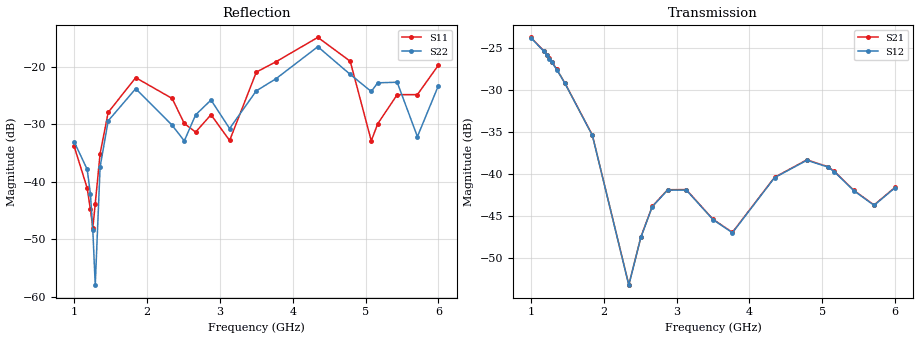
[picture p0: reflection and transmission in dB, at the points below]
!Agilent Technologies,E8364B,MY43040528,A.07.50.67
!Agilent E8364B: A.07.50.67
!Date: Sunday, March 01, 2026 16:46:23
!Correction: S11(Full 2 Port(1,2))
!S21(Full 2 Port(1,2))
!S12(Full 2 Port(1,2))
!S22(Full 2 Port(1,2))
!S2P File: Measurements: S11, S21, S12, S22:
# Hz S  dB  R 50
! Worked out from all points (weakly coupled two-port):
!   451 points, 1 GHz to 6 GHz, reference 50 ohm
!   highest |S21| = -23.77 dB at 1 GHz (marker M1); lowest = -53.3 dB at 2.344 GHz (marker M2)
!   lowest |S11| = -48.0 dB at 1.256 GHz (marker M3), VSWR 1.01, Z = 49.9 + j0.378 ohm
!   |S11| at or under -10 dB: start of sweep to end of sweep
!   |S22| runs from -59.1 to -16.4 dB; largest |S21 - S12| = 0.00031
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1e9  -33.84 31.8  -23.77 153.0  -23.81 153.1  -33.05 -1.2
1.177778e9  -41.06 49.9  -25.39 51.3  -25.43 51.4  -37.80 -5.1
1.222222e9  -44.77 65.2  -25.88 26.0  -25.92 26.1  -42.06 -10.1
1.255556e9  -48.02 107.3  -26.27 7.1  -26.31 7.2  -48.42 -14.6
1.288889e9  -43.80 155.4  -26.69 -11.8  -26.73 -11.7  -57.95 95.5
1.355556e9  -35.07 167.4  -27.58 -49.1  -27.62 -49.0  -37.39 116.5
1.466667e9  -27.91 147.2  -29.20 -110.2  -29.23 -110.2  -29.38 89.8
1.844444e9  -21.87 75.6  -35.42 47.5  -35.46 47.6  -23.79 -4.3
2.344444e9  -25.49 13.5  -53.25 -150.6  -53.29 -150.7  -30.15 -77.0
2.511111e9  -29.84 6.6  -47.52 178.8  -47.57 178.7  -32.87 -58.3
2.666667e9  -31.34 35.4  -43.90 104.3  -43.94 104.3  -28.35 -55.6
2.877778e9  -28.32 30.4  -41.92 -6.0  -41.96 -6.0  -25.76 -96.1
3.133333e9  -32.80 52.1  -41.91 -142.0  -41.96 -141.9  -30.72 -127.7
3.5e9  -20.91 47.2  -45.45 37.0  -45.48 37.2  -24.16 -128.5
3.766667e9  -19.13 21.7  -47.00 -66.1  -47.05 -66.0  -22.09 -156.5
4.344444e9  -14.87 -44.7  -40.45 22.7  -40.49 22.7  -16.49 111.7
4.788889e9  -19.02 -113.7  -38.36 133.9  -38.41 133.9  -21.31 36.2
5.077778e9  -32.86 -103.6  -39.18 -36.7  -39.22 -36.7  -24.28 40.7
5.166667e9  -29.89 -61.1  -39.74 -90.5  -39.79 -90.4  -22.77 33.5
5.433333e9  -24.83 -77.1  -42.00 100.9  -42.04 100.7  -22.67 -17.4
5.711111e9  -24.82 -60.2  -43.74 -95.8  -43.78 -95.8  -32.13 -17.6
6e9  -19.69 -73.3  -41.63 59.8  -41.68 59.8  -23.24 -16.5
